VERSION 5.7 ;
  NOWIREEXTENSIONATPIN ON ;
  DIVIDERCHAR "/" ;
  BUSBITCHARS "[]" ;
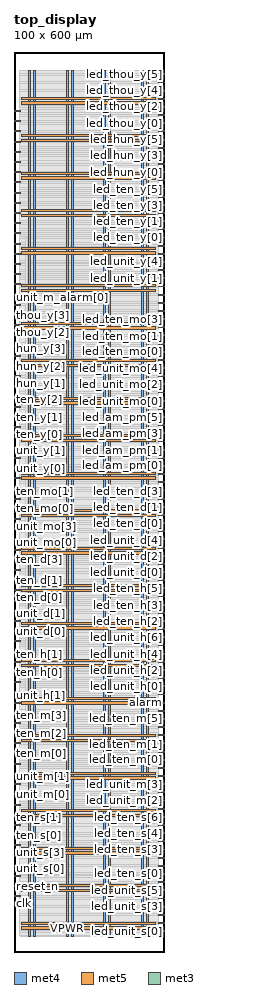
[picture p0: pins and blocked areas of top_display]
MACRO top_display
  CLASS BLOCK ;
  FOREIGN top_display ;
  ORIGIN 0.000 0.000 ;
  SIZE 100.000 BY 600.000 ;
  PIN VGND
    DIRECTION INOUT ;
    USE GROUND ;
    PORT
      LAYER met4 ;
        RECT 13.020 10.640 14.620 587.760 ;
    END
    PORT
      LAYER met4 ;
        RECT 38.020 10.640 39.620 587.760 ;
    END
    PORT
      LAYER met4 ;
        RECT 63.020 10.640 64.620 587.760 ;
    END
    PORT
      LAYER met4 ;
        RECT 88.020 10.640 89.620 587.760 ;
    END
    PORT
      LAYER met5 ;
        RECT 5.280 18.380 94.540 19.980 ;
    END
    PORT
      LAYER met5 ;
        RECT 5.280 43.380 94.540 44.980 ;
    END
    PORT
      LAYER met5 ;
        RECT 5.280 68.380 94.540 69.980 ;
    END
    PORT
      LAYER met5 ;
        RECT 5.280 93.380 94.540 94.980 ;
    END
    PORT
      LAYER met5 ;
        RECT 5.280 118.380 94.540 119.980 ;
    END
    PORT
      LAYER met5 ;
        RECT 5.280 143.380 94.540 144.980 ;
    END
    PORT
      LAYER met5 ;
        RECT 5.280 168.380 94.540 169.980 ;
    END
    PORT
      LAYER met5 ;
        RECT 5.280 193.380 94.540 194.980 ;
    END
    PORT
      LAYER met5 ;
        RECT 5.280 218.380 94.540 219.980 ;
    END
    PORT
      LAYER met5 ;
        RECT 5.280 243.380 94.540 244.980 ;
    END
    PORT
      LAYER met5 ;
        RECT 5.280 268.380 94.540 269.980 ;
    END
    PORT
      LAYER met5 ;
        RECT 5.280 293.380 94.540 294.980 ;
    END
    PORT
      LAYER met5 ;
        RECT 5.280 318.380 94.540 319.980 ;
    END
    PORT
      LAYER met5 ;
        RECT 5.280 343.380 94.540 344.980 ;
    END
    PORT
      LAYER met5 ;
        RECT 5.280 368.380 94.540 369.980 ;
    END
    PORT
      LAYER met5 ;
        RECT 5.280 393.380 94.540 394.980 ;
    END
    PORT
      LAYER met5 ;
        RECT 5.280 418.380 94.540 419.980 ;
    END
    PORT
      LAYER met5 ;
        RECT 5.280 443.380 94.540 444.980 ;
    END
    PORT
      LAYER met5 ;
        RECT 5.280 468.380 94.540 469.980 ;
    END
    PORT
      LAYER met5 ;
        RECT 5.280 493.380 94.540 494.980 ;
    END
    PORT
      LAYER met5 ;
        RECT 5.280 518.380 94.540 519.980 ;
    END
    PORT
      LAYER met5 ;
        RECT 5.280 543.380 94.540 544.980 ;
    END
    PORT
      LAYER met5 ;
        RECT 5.280 568.380 94.540 569.980 ;
    END
  END VGND
  PIN VPWR
    DIRECTION INOUT ;
    USE POWER ;
    PORT
      LAYER met4 ;
        RECT 9.720 10.640 11.320 587.760 ;
    END
    PORT
      LAYER met4 ;
        RECT 34.720 10.640 36.320 587.760 ;
    END
    PORT
      LAYER met4 ;
        RECT 59.720 10.640 61.320 587.760 ;
    END
    PORT
      LAYER met4 ;
        RECT 84.720 10.640 86.320 587.760 ;
    END
    PORT
      LAYER met5 ;
        RECT 5.280 15.080 94.540 16.680 ;
    END
    PORT
      LAYER met5 ;
        RECT 5.280 40.080 94.540 41.680 ;
    END
    PORT
      LAYER met5 ;
        RECT 5.280 65.080 94.540 66.680 ;
    END
    PORT
      LAYER met5 ;
        RECT 5.280 90.080 94.540 91.680 ;
    END
    PORT
      LAYER met5 ;
        RECT 5.280 115.080 94.540 116.680 ;
    END
    PORT
      LAYER met5 ;
        RECT 5.280 140.080 94.540 141.680 ;
    END
    PORT
      LAYER met5 ;
        RECT 5.280 165.080 94.540 166.680 ;
    END
    PORT
      LAYER met5 ;
        RECT 5.280 190.080 94.540 191.680 ;
    END
    PORT
      LAYER met5 ;
        RECT 5.280 215.080 94.540 216.680 ;
    END
    PORT
      LAYER met5 ;
        RECT 5.280 240.080 94.540 241.680 ;
    END
    PORT
      LAYER met5 ;
        RECT 5.280 265.080 94.540 266.680 ;
    END
    PORT
      LAYER met5 ;
        RECT 5.280 290.080 94.540 291.680 ;
    END
    PORT
      LAYER met5 ;
        RECT 5.280 315.080 94.540 316.680 ;
    END
    PORT
      LAYER met5 ;
        RECT 5.280 340.080 94.540 341.680 ;
    END
    PORT
      LAYER met5 ;
        RECT 5.280 365.080 94.540 366.680 ;
    END
    PORT
      LAYER met5 ;
        RECT 5.280 390.080 94.540 391.680 ;
    END
    PORT
      LAYER met5 ;
        RECT 5.280 415.080 94.540 416.680 ;
    END
    PORT
      LAYER met5 ;
        RECT 5.280 440.080 94.540 441.680 ;
    END
    PORT
      LAYER met5 ;
        RECT 5.280 465.080 94.540 466.680 ;
    END
    PORT
      LAYER met5 ;
        RECT 5.280 490.080 94.540 491.680 ;
    END
    PORT
      LAYER met5 ;
        RECT 5.280 515.080 94.540 516.680 ;
    END
    PORT
      LAYER met5 ;
        RECT 5.280 540.080 94.540 541.680 ;
    END
    PORT
      LAYER met5 ;
        RECT 5.280 565.080 94.540 566.680 ;
    END
  END VPWR
  PIN alarm
    DIRECTION OUTPUT ;
    USE SIGNAL ;
    ANTENNADIFFAREA 0.445500 ;
    PORT
      LAYER met3 ;
        RECT 96.000 165.960 100.000 166.560 ;
    END
  END alarm
  PIN clk
    DIRECTION INPUT ;
    USE SIGNAL ;
    PORT
      LAYER met3 ;
        RECT 0.000 36.760 4.000 37.360 ;
    END
  END clk
  PIN hun_y[0]
    DIRECTION INPUT ;
    USE SIGNAL ;
    ANTENNAGATEAREA 0.159000 ;
    PORT
      LAYER met3 ;
        RECT 0.000 376.760 4.000 377.360 ;
    END
  END hun_y[0]
  PIN hun_y[1]
    DIRECTION INPUT ;
    USE SIGNAL ;
    ANTENNAGATEAREA 0.213000 ;
    PORT
      LAYER met3 ;
        RECT 0.000 383.560 4.000 384.160 ;
    END
  END hun_y[1]
  PIN hun_y[2]
    DIRECTION INPUT ;
    USE SIGNAL ;
    ANTENNAGATEAREA 0.213000 ;
    PORT
      LAYER met3 ;
        RECT 0.000 390.360 4.000 390.960 ;
    END
  END hun_y[2]
  PIN hun_y[3]
    DIRECTION INPUT ;
    USE SIGNAL ;
    ANTENNAGATEAREA 0.213000 ;
    PORT
      LAYER met3 ;
        RECT 0.000 397.160 4.000 397.760 ;
    END
  END hun_y[3]
  PIN led_am_pm[0]
    DIRECTION OUTPUT ;
    USE SIGNAL ;
    ANTENNADIFFAREA 0.445500 ;
    PORT
      LAYER met3 ;
        RECT 96.000 323.720 100.000 324.320 ;
    END
  END led_am_pm[0]
  PIN led_am_pm[1]
    DIRECTION OUTPUT ;
    USE SIGNAL ;
    ANTENNADIFFAREA 0.445500 ;
    PORT
      LAYER met3 ;
        RECT 96.000 329.160 100.000 329.760 ;
    END
  END led_am_pm[1]
  PIN led_am_pm[2]
    DIRECTION OUTPUT ;
    USE SIGNAL ;
    ANTENNADIFFAREA 0.445500 ;
    PORT
      LAYER met3 ;
        RECT 96.000 334.600 100.000 335.200 ;
    END
  END led_am_pm[2]
  PIN led_am_pm[3]
    DIRECTION OUTPUT ;
    USE SIGNAL ;
    ANTENNADIFFAREA 0.445500 ;
    PORT
      LAYER met3 ;
        RECT 96.000 340.040 100.000 340.640 ;
    END
  END led_am_pm[3]
  PIN led_am_pm[4]
    DIRECTION OUTPUT ;
    USE SIGNAL ;
    PORT
      LAYER met3 ;
        RECT 96.000 345.480 100.000 346.080 ;
    END
  END led_am_pm[4]
  PIN led_am_pm[5]
    DIRECTION OUTPUT ;
    USE SIGNAL ;
    ANTENNADIFFAREA 0.445500 ;
    PORT
      LAYER met3 ;
        RECT 96.000 350.920 100.000 351.520 ;
    END
  END led_am_pm[5]
  PIN led_am_pm[6]
    DIRECTION OUTPUT ;
    USE SIGNAL ;
    ANTENNADIFFAREA 0.445500 ;
    PORT
      LAYER met3 ;
        RECT 96.000 356.360 100.000 356.960 ;
    END
  END led_am_pm[6]
  PIN led_hun_y[0]
    DIRECTION OUTPUT ;
    USE SIGNAL ;
    ANTENNADIFFAREA 0.445500 ;
    PORT
      LAYER met3 ;
        RECT 96.000 514.120 100.000 514.720 ;
    END
  END led_hun_y[0]
  PIN led_hun_y[1]
    DIRECTION OUTPUT ;
    USE SIGNAL ;
    ANTENNADIFFAREA 0.445500 ;
    PORT
      LAYER met3 ;
        RECT 96.000 519.560 100.000 520.160 ;
    END
  END led_hun_y[1]
  PIN led_hun_y[2]
    DIRECTION OUTPUT ;
    USE SIGNAL ;
    ANTENNADIFFAREA 0.445500 ;
    PORT
      LAYER met3 ;
        RECT 96.000 525.000 100.000 525.600 ;
    END
  END led_hun_y[2]
  PIN led_hun_y[3]
    DIRECTION OUTPUT ;
    USE SIGNAL ;
    ANTENNADIFFAREA 0.445500 ;
    PORT
      LAYER met3 ;
        RECT 96.000 530.440 100.000 531.040 ;
    END
  END led_hun_y[3]
  PIN led_hun_y[4]
    DIRECTION OUTPUT ;
    USE SIGNAL ;
    ANTENNADIFFAREA 0.445500 ;
    PORT
      LAYER met3 ;
        RECT 96.000 535.880 100.000 536.480 ;
    END
  END led_hun_y[4]
  PIN led_hun_y[5]
    DIRECTION OUTPUT ;
    USE SIGNAL ;
    ANTENNADIFFAREA 0.445500 ;
    PORT
      LAYER met3 ;
        RECT 96.000 541.320 100.000 541.920 ;
    END
  END led_hun_y[5]
  PIN led_hun_y[6]
    DIRECTION OUTPUT ;
    USE SIGNAL ;
    ANTENNADIFFAREA 0.445500 ;
    PORT
      LAYER met3 ;
        RECT 96.000 546.760 100.000 547.360 ;
    END
  END led_hun_y[6]
  PIN led_ten_d[0]
    DIRECTION OUTPUT ;
    USE SIGNAL ;
    ANTENNADIFFAREA 0.445500 ;
    PORT
      LAYER met3 ;
        RECT 96.000 285.640 100.000 286.240 ;
    END
  END led_ten_d[0]
  PIN led_ten_d[1]
    DIRECTION OUTPUT ;
    USE SIGNAL ;
    ANTENNADIFFAREA 0.445500 ;
    PORT
      LAYER met3 ;
        RECT 96.000 291.080 100.000 291.680 ;
    END
  END led_ten_d[1]
  PIN led_ten_d[2]
    DIRECTION OUTPUT ;
    USE SIGNAL ;
    ANTENNADIFFAREA 0.445500 ;
    PORT
      LAYER met3 ;
        RECT 96.000 296.520 100.000 297.120 ;
    END
  END led_ten_d[2]
  PIN led_ten_d[3]
    DIRECTION OUTPUT ;
    USE SIGNAL ;
    ANTENNADIFFAREA 0.445500 ;
    PORT
      LAYER met3 ;
        RECT 96.000 301.960 100.000 302.560 ;
    END
  END led_ten_d[3]
  PIN led_ten_d[4]
    DIRECTION OUTPUT ;
    USE SIGNAL ;
    ANTENNADIFFAREA 0.445500 ;
    PORT
      LAYER met3 ;
        RECT 96.000 307.400 100.000 308.000 ;
    END
  END led_ten_d[4]
  PIN led_ten_d[5]
    DIRECTION OUTPUT ;
    USE SIGNAL ;
    ANTENNADIFFAREA 0.445500 ;
    PORT
      LAYER met3 ;
        RECT 96.000 312.840 100.000 313.440 ;
    END
  END led_ten_d[5]
  PIN led_ten_d[6]
    DIRECTION OUTPUT ;
    USE SIGNAL ;
    ANTENNADIFFAREA 0.445500 ;
    PORT
      LAYER met3 ;
        RECT 96.000 318.280 100.000 318.880 ;
    END
  END led_ten_d[6]
  PIN led_ten_h[0]
    DIRECTION OUTPUT ;
    USE SIGNAL ;
    ANTENNADIFFAREA 0.445500 ;
    PORT
      LAYER met3 ;
        RECT 96.000 209.480 100.000 210.080 ;
    END
  END led_ten_h[0]
  PIN led_ten_h[1]
    DIRECTION OUTPUT ;
    USE SIGNAL ;
    ANTENNADIFFAREA 0.445500 ;
    PORT
      LAYER met3 ;
        RECT 96.000 214.920 100.000 215.520 ;
    END
  END led_ten_h[1]
  PIN led_ten_h[2]
    DIRECTION OUTPUT ;
    USE SIGNAL ;
    ANTENNADIFFAREA 0.445500 ;
    PORT
      LAYER met3 ;
        RECT 96.000 220.360 100.000 220.960 ;
    END
  END led_ten_h[2]
  PIN led_ten_h[3]
    DIRECTION OUTPUT ;
    USE SIGNAL ;
    ANTENNADIFFAREA 0.445500 ;
    PORT
      LAYER met3 ;
        RECT 96.000 225.800 100.000 226.400 ;
    END
  END led_ten_h[3]
  PIN led_ten_h[4]
    DIRECTION OUTPUT ;
    USE SIGNAL ;
    ANTENNADIFFAREA 0.445500 ;
    PORT
      LAYER met3 ;
        RECT 96.000 231.240 100.000 231.840 ;
    END
  END led_ten_h[4]
  PIN led_ten_h[5]
    DIRECTION OUTPUT ;
    USE SIGNAL ;
    ANTENNADIFFAREA 0.445500 ;
    PORT
      LAYER met3 ;
        RECT 96.000 236.680 100.000 237.280 ;
    END
  END led_ten_h[5]
  PIN led_ten_h[6]
    DIRECTION OUTPUT ;
    USE SIGNAL ;
    ANTENNADIFFAREA 0.445500 ;
    PORT
      LAYER met3 ;
        RECT 96.000 242.120 100.000 242.720 ;
    END
  END led_ten_h[6]
  PIN led_ten_m[0]
    DIRECTION OUTPUT ;
    USE SIGNAL ;
    ANTENNADIFFAREA 0.445500 ;
    PORT
      LAYER met3 ;
        RECT 96.000 127.880 100.000 128.480 ;
    END
  END led_ten_m[0]
  PIN led_ten_m[1]
    DIRECTION OUTPUT ;
    USE SIGNAL ;
    ANTENNADIFFAREA 0.445500 ;
    PORT
      LAYER met3 ;
        RECT 96.000 133.320 100.000 133.920 ;
    END
  END led_ten_m[1]
  PIN led_ten_m[2]
    DIRECTION OUTPUT ;
    USE SIGNAL ;
    ANTENNADIFFAREA 0.445500 ;
    PORT
      LAYER met3 ;
        RECT 96.000 138.760 100.000 139.360 ;
    END
  END led_ten_m[2]
  PIN led_ten_m[3]
    DIRECTION OUTPUT ;
    USE SIGNAL ;
    ANTENNADIFFAREA 0.445500 ;
    PORT
      LAYER met3 ;
        RECT 96.000 144.200 100.000 144.800 ;
    END
  END led_ten_m[3]
  PIN led_ten_m[4]
    DIRECTION OUTPUT ;
    USE SIGNAL ;
    ANTENNADIFFAREA 0.445500 ;
    PORT
      LAYER met3 ;
        RECT 96.000 149.640 100.000 150.240 ;
    END
  END led_ten_m[4]
  PIN led_ten_m[5]
    DIRECTION OUTPUT ;
    USE SIGNAL ;
    ANTENNADIFFAREA 0.445500 ;
    PORT
      LAYER met3 ;
        RECT 96.000 155.080 100.000 155.680 ;
    END
  END led_ten_m[5]
  PIN led_ten_m[6]
    DIRECTION OUTPUT ;
    USE SIGNAL ;
    ANTENNADIFFAREA 0.445500 ;
    PORT
      LAYER met3 ;
        RECT 96.000 160.520 100.000 161.120 ;
    END
  END led_ten_m[6]
  PIN led_ten_mo[0]
    DIRECTION OUTPUT ;
    USE SIGNAL ;
    ANTENNADIFFAREA 0.445500 ;
    PORT
      LAYER met3 ;
        RECT 96.000 399.880 100.000 400.480 ;
    END
  END led_ten_mo[0]
  PIN led_ten_mo[1]
    DIRECTION OUTPUT ;
    USE SIGNAL ;
    ANTENNADIFFAREA 0.445500 ;
    PORT
      LAYER met3 ;
        RECT 96.000 405.320 100.000 405.920 ;
    END
  END led_ten_mo[1]
  PIN led_ten_mo[2]
    DIRECTION OUTPUT ;
    USE SIGNAL ;
    ANTENNADIFFAREA 0.445500 ;
    PORT
      LAYER met3 ;
        RECT 96.000 410.760 100.000 411.360 ;
    END
  END led_ten_mo[2]
  PIN led_ten_mo[3]
    DIRECTION OUTPUT ;
    USE SIGNAL ;
    ANTENNADIFFAREA 0.445500 ;
    PORT
      LAYER met3 ;
        RECT 96.000 416.200 100.000 416.800 ;
    END
  END led_ten_mo[3]
  PIN led_ten_mo[4]
    DIRECTION OUTPUT ;
    USE SIGNAL ;
    ANTENNADIFFAREA 0.445500 ;
    PORT
      LAYER met3 ;
        RECT 96.000 421.640 100.000 422.240 ;
    END
  END led_ten_mo[4]
  PIN led_ten_mo[5]
    DIRECTION OUTPUT ;
    USE SIGNAL ;
    ANTENNADIFFAREA 0.445500 ;
    PORT
      LAYER met3 ;
        RECT 96.000 427.080 100.000 427.680 ;
    END
  END led_ten_mo[5]
  PIN led_ten_mo[6]
    DIRECTION OUTPUT ;
    USE SIGNAL ;
    ANTENNADIFFAREA 0.445500 ;
    PORT
      LAYER met3 ;
        RECT 96.000 432.520 100.000 433.120 ;
    END
  END led_ten_mo[6]
  PIN led_ten_s[0]
    DIRECTION OUTPUT ;
    USE SIGNAL ;
    ANTENNADIFFAREA 0.445500 ;
    PORT
      LAYER met3 ;
        RECT 96.000 51.720 100.000 52.320 ;
    END
  END led_ten_s[0]
  PIN led_ten_s[1]
    DIRECTION OUTPUT ;
    USE SIGNAL ;
    ANTENNADIFFAREA 0.445500 ;
    PORT
      LAYER met3 ;
        RECT 96.000 57.160 100.000 57.760 ;
    END
  END led_ten_s[1]
  PIN led_ten_s[2]
    DIRECTION OUTPUT ;
    USE SIGNAL ;
    ANTENNADIFFAREA 0.445500 ;
    PORT
      LAYER met3 ;
        RECT 96.000 62.600 100.000 63.200 ;
    END
  END led_ten_s[2]
  PIN led_ten_s[3]
    DIRECTION OUTPUT ;
    USE SIGNAL ;
    ANTENNADIFFAREA 0.445500 ;
    PORT
      LAYER met3 ;
        RECT 96.000 68.040 100.000 68.640 ;
    END
  END led_ten_s[3]
  PIN led_ten_s[4]
    DIRECTION OUTPUT ;
    USE SIGNAL ;
    ANTENNADIFFAREA 0.445500 ;
    PORT
      LAYER met3 ;
        RECT 96.000 73.480 100.000 74.080 ;
    END
  END led_ten_s[4]
  PIN led_ten_s[5]
    DIRECTION OUTPUT ;
    USE SIGNAL ;
    ANTENNADIFFAREA 0.445500 ;
    PORT
      LAYER met3 ;
        RECT 96.000 78.920 100.000 79.520 ;
    END
  END led_ten_s[5]
  PIN led_ten_s[6]
    DIRECTION OUTPUT ;
    USE SIGNAL ;
    ANTENNADIFFAREA 0.445500 ;
    PORT
      LAYER met3 ;
        RECT 96.000 84.360 100.000 84.960 ;
    END
  END led_ten_s[6]
  PIN led_ten_y[0]
    DIRECTION OUTPUT ;
    USE SIGNAL ;
    ANTENNADIFFAREA 0.445500 ;
    PORT
      LAYER met3 ;
        RECT 96.000 476.040 100.000 476.640 ;
    END
  END led_ten_y[0]
  PIN led_ten_y[1]
    DIRECTION OUTPUT ;
    USE SIGNAL ;
    ANTENNADIFFAREA 0.445500 ;
    PORT
      LAYER met3 ;
        RECT 96.000 481.480 100.000 482.080 ;
    END
  END led_ten_y[1]
  PIN led_ten_y[2]
    DIRECTION OUTPUT ;
    USE SIGNAL ;
    ANTENNADIFFAREA 0.445500 ;
    PORT
      LAYER met3 ;
        RECT 96.000 486.920 100.000 487.520 ;
    END
  END led_ten_y[2]
  PIN led_ten_y[3]
    DIRECTION OUTPUT ;
    USE SIGNAL ;
    ANTENNADIFFAREA 0.445500 ;
    PORT
      LAYER met3 ;
        RECT 96.000 492.360 100.000 492.960 ;
    END
  END led_ten_y[3]
  PIN led_ten_y[4]
    DIRECTION OUTPUT ;
    USE SIGNAL ;
    ANTENNADIFFAREA 0.445500 ;
    PORT
      LAYER met3 ;
        RECT 96.000 497.800 100.000 498.400 ;
    END
  END led_ten_y[4]
  PIN led_ten_y[5]
    DIRECTION OUTPUT ;
    USE SIGNAL ;
    ANTENNADIFFAREA 0.445500 ;
    PORT
      LAYER met3 ;
        RECT 96.000 503.240 100.000 503.840 ;
    END
  END led_ten_y[5]
  PIN led_ten_y[6]
    DIRECTION OUTPUT ;
    USE SIGNAL ;
    ANTENNADIFFAREA 0.445500 ;
    PORT
      LAYER met3 ;
        RECT 96.000 508.680 100.000 509.280 ;
    END
  END led_ten_y[6]
  PIN led_thou_y[0]
    DIRECTION OUTPUT ;
    USE SIGNAL ;
    ANTENNADIFFAREA 0.445500 ;
    PORT
      LAYER met3 ;
        RECT 96.000 552.200 100.000 552.800 ;
    END
  END led_thou_y[0]
  PIN led_thou_y[1]
    DIRECTION OUTPUT ;
    USE SIGNAL ;
    ANTENNADIFFAREA 0.445500 ;
    PORT
      LAYER met3 ;
        RECT 96.000 557.640 100.000 558.240 ;
    END
  END led_thou_y[1]
  PIN led_thou_y[2]
    DIRECTION OUTPUT ;
    USE SIGNAL ;
    ANTENNADIFFAREA 0.445500 ;
    PORT
      LAYER met3 ;
        RECT 96.000 563.080 100.000 563.680 ;
    END
  END led_thou_y[2]
  PIN led_thou_y[3]
    DIRECTION OUTPUT ;
    USE SIGNAL ;
    ANTENNADIFFAREA 0.445500 ;
    PORT
      LAYER met3 ;
        RECT 96.000 568.520 100.000 569.120 ;
    END
  END led_thou_y[3]
  PIN led_thou_y[4]
    DIRECTION OUTPUT ;
    USE SIGNAL ;
    ANTENNADIFFAREA 0.445500 ;
    PORT
      LAYER met3 ;
        RECT 96.000 573.960 100.000 574.560 ;
    END
  END led_thou_y[4]
  PIN led_thou_y[5]
    DIRECTION OUTPUT ;
    USE SIGNAL ;
    ANTENNADIFFAREA 0.445500 ;
    PORT
      LAYER met3 ;
        RECT 96.000 579.400 100.000 580.000 ;
    END
  END led_thou_y[5]
  PIN led_thou_y[6]
    DIRECTION OUTPUT ;
    USE SIGNAL ;
    ANTENNADIFFAREA 0.445500 ;
    PORT
      LAYER met3 ;
        RECT 96.000 584.840 100.000 585.440 ;
    END
  END led_thou_y[6]
  PIN led_unit_d[0]
    DIRECTION OUTPUT ;
    USE SIGNAL ;
    ANTENNADIFFAREA 0.445500 ;
    PORT
      LAYER met3 ;
        RECT 96.000 247.560 100.000 248.160 ;
    END
  END led_unit_d[0]
  PIN led_unit_d[1]
    DIRECTION OUTPUT ;
    USE SIGNAL ;
    ANTENNADIFFAREA 0.445500 ;
    PORT
      LAYER met3 ;
        RECT 96.000 253.000 100.000 253.600 ;
    END
  END led_unit_d[1]
  PIN led_unit_d[2]
    DIRECTION OUTPUT ;
    USE SIGNAL ;
    ANTENNADIFFAREA 0.445500 ;
    PORT
      LAYER met3 ;
        RECT 96.000 258.440 100.000 259.040 ;
    END
  END led_unit_d[2]
  PIN led_unit_d[3]
    DIRECTION OUTPUT ;
    USE SIGNAL ;
    ANTENNADIFFAREA 0.445500 ;
    PORT
      LAYER met3 ;
        RECT 96.000 263.880 100.000 264.480 ;
    END
  END led_unit_d[3]
  PIN led_unit_d[4]
    DIRECTION OUTPUT ;
    USE SIGNAL ;
    ANTENNADIFFAREA 0.445500 ;
    PORT
      LAYER met3 ;
        RECT 96.000 269.320 100.000 269.920 ;
    END
  END led_unit_d[4]
  PIN led_unit_d[5]
    DIRECTION OUTPUT ;
    USE SIGNAL ;
    ANTENNADIFFAREA 0.445500 ;
    PORT
      LAYER met3 ;
        RECT 96.000 274.760 100.000 275.360 ;
    END
  END led_unit_d[5]
  PIN led_unit_d[6]
    DIRECTION OUTPUT ;
    USE SIGNAL ;
    ANTENNADIFFAREA 0.445500 ;
    PORT
      LAYER met3 ;
        RECT 96.000 280.200 100.000 280.800 ;
    END
  END led_unit_d[6]
  PIN led_unit_h[0]
    DIRECTION OUTPUT ;
    USE SIGNAL ;
    ANTENNADIFFAREA 0.445500 ;
    PORT
      LAYER met3 ;
        RECT 96.000 171.400 100.000 172.000 ;
    END
  END led_unit_h[0]
  PIN led_unit_h[1]
    DIRECTION OUTPUT ;
    USE SIGNAL ;
    ANTENNADIFFAREA 0.445500 ;
    PORT
      LAYER met3 ;
        RECT 96.000 176.840 100.000 177.440 ;
    END
  END led_unit_h[1]
  PIN led_unit_h[2]
    DIRECTION OUTPUT ;
    USE SIGNAL ;
    ANTENNADIFFAREA 0.445500 ;
    PORT
      LAYER met3 ;
        RECT 96.000 182.280 100.000 182.880 ;
    END
  END led_unit_h[2]
  PIN led_unit_h[3]
    DIRECTION OUTPUT ;
    USE SIGNAL ;
    ANTENNADIFFAREA 0.445500 ;
    PORT
      LAYER met3 ;
        RECT 96.000 187.720 100.000 188.320 ;
    END
  END led_unit_h[3]
  PIN led_unit_h[4]
    DIRECTION OUTPUT ;
    USE SIGNAL ;
    ANTENNADIFFAREA 0.445500 ;
    PORT
      LAYER met3 ;
        RECT 96.000 193.160 100.000 193.760 ;
    END
  END led_unit_h[4]
  PIN led_unit_h[5]
    DIRECTION OUTPUT ;
    USE SIGNAL ;
    ANTENNADIFFAREA 0.445500 ;
    PORT
      LAYER met3 ;
        RECT 96.000 198.600 100.000 199.200 ;
    END
  END led_unit_h[5]
  PIN led_unit_h[6]
    DIRECTION OUTPUT ;
    USE SIGNAL ;
    ANTENNADIFFAREA 0.445500 ;
    PORT
      LAYER met3 ;
        RECT 96.000 204.040 100.000 204.640 ;
    END
  END led_unit_h[6]
  PIN led_unit_m[0]
    DIRECTION OUTPUT ;
    USE SIGNAL ;
    ANTENNADIFFAREA 0.445500 ;
    PORT
      LAYER met3 ;
        RECT 96.000 89.800 100.000 90.400 ;
    END
  END led_unit_m[0]
  PIN led_unit_m[1]
    DIRECTION OUTPUT ;
    USE SIGNAL ;
    ANTENNADIFFAREA 0.445500 ;
    PORT
      LAYER met3 ;
        RECT 96.000 95.240 100.000 95.840 ;
    END
  END led_unit_m[1]
  PIN led_unit_m[2]
    DIRECTION OUTPUT ;
    USE SIGNAL ;
    ANTENNADIFFAREA 0.445500 ;
    PORT
      LAYER met3 ;
        RECT 96.000 100.680 100.000 101.280 ;
    END
  END led_unit_m[2]
  PIN led_unit_m[3]
    DIRECTION OUTPUT ;
    USE SIGNAL ;
    ANTENNADIFFAREA 0.445500 ;
    PORT
      LAYER met3 ;
        RECT 96.000 106.120 100.000 106.720 ;
    END
  END led_unit_m[3]
  PIN led_unit_m[4]
    DIRECTION OUTPUT ;
    USE SIGNAL ;
    ANTENNADIFFAREA 0.445500 ;
    PORT
      LAYER met3 ;
        RECT 96.000 111.560 100.000 112.160 ;
    END
  END led_unit_m[4]
  PIN led_unit_m[5]
    DIRECTION OUTPUT ;
    USE SIGNAL ;
    ANTENNADIFFAREA 0.445500 ;
    PORT
      LAYER met3 ;
        RECT 96.000 117.000 100.000 117.600 ;
    END
  END led_unit_m[5]
  PIN led_unit_m[6]
    DIRECTION OUTPUT ;
    USE SIGNAL ;
    ANTENNADIFFAREA 0.445500 ;
    PORT
      LAYER met3 ;
        RECT 96.000 122.440 100.000 123.040 ;
    END
  END led_unit_m[6]
  PIN led_unit_mo[0]
    DIRECTION OUTPUT ;
    USE SIGNAL ;
    ANTENNADIFFAREA 0.445500 ;
    PORT
      LAYER met3 ;
        RECT 96.000 361.800 100.000 362.400 ;
    END
  END led_unit_mo[0]
  PIN led_unit_mo[1]
    DIRECTION OUTPUT ;
    USE SIGNAL ;
    ANTENNADIFFAREA 0.445500 ;
    PORT
      LAYER met3 ;
        RECT 96.000 367.240 100.000 367.840 ;
    END
  END led_unit_mo[1]
  PIN led_unit_mo[2]
    DIRECTION OUTPUT ;
    USE SIGNAL ;
    ANTENNADIFFAREA 0.445500 ;
    PORT
      LAYER met3 ;
        RECT 96.000 372.680 100.000 373.280 ;
    END
  END led_unit_mo[2]
  PIN led_unit_mo[3]
    DIRECTION OUTPUT ;
    USE SIGNAL ;
    ANTENNADIFFAREA 0.445500 ;
    PORT
      LAYER met3 ;
        RECT 96.000 378.120 100.000 378.720 ;
    END
  END led_unit_mo[3]
  PIN led_unit_mo[4]
    DIRECTION OUTPUT ;
    USE SIGNAL ;
    ANTENNADIFFAREA 0.445500 ;
    PORT
      LAYER met3 ;
        RECT 96.000 383.560 100.000 384.160 ;
    END
  END led_unit_mo[4]
  PIN led_unit_mo[5]
    DIRECTION OUTPUT ;
    USE SIGNAL ;
    ANTENNADIFFAREA 0.445500 ;
    PORT
      LAYER met3 ;
        RECT 96.000 389.000 100.000 389.600 ;
    END
  END led_unit_mo[5]
  PIN led_unit_mo[6]
    DIRECTION OUTPUT ;
    USE SIGNAL ;
    ANTENNADIFFAREA 0.445500 ;
    PORT
      LAYER met3 ;
        RECT 96.000 394.440 100.000 395.040 ;
    END
  END led_unit_mo[6]
  PIN led_unit_s[0]
    DIRECTION OUTPUT ;
    USE SIGNAL ;
    ANTENNADIFFAREA 0.445500 ;
    PORT
      LAYER met3 ;
        RECT 96.000 13.640 100.000 14.240 ;
    END
  END led_unit_s[0]
  PIN led_unit_s[1]
    DIRECTION OUTPUT ;
    USE SIGNAL ;
    ANTENNADIFFAREA 0.445500 ;
    PORT
      LAYER met3 ;
        RECT 96.000 19.080 100.000 19.680 ;
    END
  END led_unit_s[1]
  PIN led_unit_s[2]
    DIRECTION OUTPUT ;
    USE SIGNAL ;
    ANTENNADIFFAREA 0.445500 ;
    PORT
      LAYER met3 ;
        RECT 96.000 24.520 100.000 25.120 ;
    END
  END led_unit_s[2]
  PIN led_unit_s[3]
    DIRECTION OUTPUT ;
    USE SIGNAL ;
    ANTENNADIFFAREA 0.445500 ;
    PORT
      LAYER met3 ;
        RECT 96.000 29.960 100.000 30.560 ;
    END
  END led_unit_s[3]
  PIN led_unit_s[4]
    DIRECTION OUTPUT ;
    USE SIGNAL ;
    ANTENNADIFFAREA 0.445500 ;
    PORT
      LAYER met3 ;
        RECT 96.000 35.400 100.000 36.000 ;
    END
  END led_unit_s[4]
  PIN led_unit_s[5]
    DIRECTION OUTPUT ;
    USE SIGNAL ;
    ANTENNADIFFAREA 0.445500 ;
    PORT
      LAYER met3 ;
        RECT 96.000 40.840 100.000 41.440 ;
    END
  END led_unit_s[5]
  PIN led_unit_s[6]
    DIRECTION OUTPUT ;
    USE SIGNAL ;
    ANTENNADIFFAREA 0.445500 ;
    PORT
      LAYER met3 ;
        RECT 96.000 46.280 100.000 46.880 ;
    END
  END led_unit_s[6]
  PIN led_unit_y[0]
    DIRECTION OUTPUT ;
    USE SIGNAL ;
    ANTENNADIFFAREA 0.445500 ;
    PORT
      LAYER met3 ;
        RECT 96.000 437.960 100.000 438.560 ;
    END
  END led_unit_y[0]
  PIN led_unit_y[1]
    DIRECTION OUTPUT ;
    USE SIGNAL ;
    ANTENNADIFFAREA 0.445500 ;
    PORT
      LAYER met3 ;
        RECT 96.000 443.400 100.000 444.000 ;
    END
  END led_unit_y[1]
  PIN led_unit_y[2]
    DIRECTION OUTPUT ;
    USE SIGNAL ;
    ANTENNADIFFAREA 0.445500 ;
    PORT
      LAYER met3 ;
        RECT 96.000 448.840 100.000 449.440 ;
    END
  END led_unit_y[2]
  PIN led_unit_y[3]
    DIRECTION OUTPUT ;
    USE SIGNAL ;
    ANTENNADIFFAREA 0.445500 ;
    PORT
      LAYER met3 ;
        RECT 96.000 454.280 100.000 454.880 ;
    END
  END led_unit_y[3]
  PIN led_unit_y[4]
    DIRECTION OUTPUT ;
    USE SIGNAL ;
    ANTENNADIFFAREA 0.445500 ;
    PORT
      LAYER met3 ;
        RECT 96.000 459.720 100.000 460.320 ;
    END
  END led_unit_y[4]
  PIN led_unit_y[5]
    DIRECTION OUTPUT ;
    USE SIGNAL ;
    ANTENNADIFFAREA 0.445500 ;
    PORT
      LAYER met3 ;
        RECT 96.000 465.160 100.000 465.760 ;
    END
  END led_unit_y[5]
  PIN led_unit_y[6]
    DIRECTION OUTPUT ;
    USE SIGNAL ;
    ANTENNADIFFAREA 0.445500 ;
    PORT
      LAYER met3 ;
        RECT 96.000 470.600 100.000 471.200 ;
    END
  END led_unit_y[6]
  PIN mode_alarm[0]
    DIRECTION INPUT ;
    USE SIGNAL ;
    PORT
      LAYER met3 ;
        RECT 0.000 539.960 4.000 540.560 ;
    END
  END mode_alarm[0]
  PIN mode_alarm[1]
    DIRECTION INPUT ;
    USE SIGNAL ;
    PORT
      LAYER met3 ;
        RECT 0.000 546.760 4.000 547.360 ;
    END
  END mode_alarm[1]
  PIN mode_display[0]
    DIRECTION INPUT ;
    USE SIGNAL ;
    ANTENNAGATEAREA 0.196500 ;
    PORT
      LAYER met3 ;
        RECT 0.000 553.560 4.000 554.160 ;
    END
  END mode_display[0]
  PIN mode_display[1]
    DIRECTION INPUT ;
    USE SIGNAL ;
    ANTENNAGATEAREA 0.196500 ;
    PORT
      LAYER met3 ;
        RECT 0.000 560.360 4.000 560.960 ;
    END
  END mode_display[1]
  PIN reset_n
    DIRECTION INPUT ;
    USE SIGNAL ;
    PORT
      LAYER met3 ;
        RECT 0.000 43.560 4.000 44.160 ;
    END
  END reset_n
  PIN ten_d[0]
    DIRECTION INPUT ;
    USE SIGNAL ;
    ANTENNAGATEAREA 0.213000 ;
    PORT
      LAYER met3 ;
        RECT 0.000 240.760 4.000 241.360 ;
    END
  END ten_d[0]
  PIN ten_d[1]
    DIRECTION INPUT ;
    USE SIGNAL ;
    ANTENNAGATEAREA 0.159000 ;
    PORT
      LAYER met3 ;
        RECT 0.000 247.560 4.000 248.160 ;
    END
  END ten_d[1]
  PIN ten_d[2]
    DIRECTION INPUT ;
    USE SIGNAL ;
    ANTENNAGATEAREA 0.213000 ;
    PORT
      LAYER met3 ;
        RECT 0.000 254.360 4.000 254.960 ;
    END
  END ten_d[2]
  PIN ten_d[3]
    DIRECTION INPUT ;
    USE SIGNAL ;
    ANTENNAGATEAREA 0.159000 ;
    PORT
      LAYER met3 ;
        RECT 0.000 261.160 4.000 261.760 ;
    END
  END ten_d[3]
  PIN ten_h[0]
    DIRECTION INPUT ;
    USE SIGNAL ;
    ANTENNAGATEAREA 0.159000 ;
    PORT
      LAYER met3 ;
        RECT 0.000 186.360 4.000 186.960 ;
    END
  END ten_h[0]
  PIN ten_h[1]
    DIRECTION INPUT ;
    USE SIGNAL ;
    ANTENNAGATEAREA 0.213000 ;
    PORT
      LAYER met3 ;
        RECT 0.000 193.160 4.000 193.760 ;
    END
  END ten_h[1]
  PIN ten_h[2]
    DIRECTION INPUT ;
    USE SIGNAL ;
    ANTENNAGATEAREA 0.159000 ;
    PORT
      LAYER met3 ;
        RECT 0.000 199.960 4.000 200.560 ;
    END
  END ten_h[2]
  PIN ten_h[3]
    DIRECTION INPUT ;
    USE SIGNAL ;
    ANTENNAGATEAREA 0.213000 ;
    PORT
      LAYER met3 ;
        RECT 0.000 206.760 4.000 207.360 ;
    END
  END ten_h[3]
  PIN ten_h_alarm[0]
    DIRECTION INPUT ;
    USE SIGNAL ;
    ANTENNAGATEAREA 0.213000 ;
    PORT
      LAYER met3 ;
        RECT 0.000 512.760 4.000 513.360 ;
    END
  END ten_h_alarm[0]
  PIN ten_h_alarm[1]
    DIRECTION INPUT ;
    USE SIGNAL ;
    ANTENNAGATEAREA 0.159000 ;
    PORT
      LAYER met3 ;
        RECT 0.000 519.560 4.000 520.160 ;
    END
  END ten_h_alarm[1]
  PIN ten_h_alarm[2]
    DIRECTION INPUT ;
    USE SIGNAL ;
    ANTENNAGATEAREA 0.159000 ;
    PORT
      LAYER met3 ;
        RECT 0.000 526.360 4.000 526.960 ;
    END
  END ten_h_alarm[2]
  PIN ten_h_alarm[3]
    DIRECTION INPUT ;
    USE SIGNAL ;
    ANTENNAGATEAREA 0.159000 ;
    PORT
      LAYER met3 ;
        RECT 0.000 533.160 4.000 533.760 ;
    END
  END ten_h_alarm[3]
  PIN ten_m[0]
    DIRECTION INPUT ;
    USE SIGNAL ;
    ANTENNAGATEAREA 0.159000 ;
    PORT
      LAYER met3 ;
        RECT 0.000 131.960 4.000 132.560 ;
    END
  END ten_m[0]
  PIN ten_m[1]
    DIRECTION INPUT ;
    USE SIGNAL ;
    ANTENNAGATEAREA 0.213000 ;
    PORT
      LAYER met3 ;
        RECT 0.000 138.760 4.000 139.360 ;
    END
  END ten_m[1]
  PIN ten_m[2]
    DIRECTION INPUT ;
    USE SIGNAL ;
    ANTENNAGATEAREA 0.213000 ;
    PORT
      LAYER met3 ;
        RECT 0.000 145.560 4.000 146.160 ;
    END
  END ten_m[2]
  PIN ten_m[3]
    DIRECTION INPUT ;
    USE SIGNAL ;
    ANTENNAGATEAREA 0.196500 ;
    PORT
      LAYER met3 ;
        RECT 0.000 152.360 4.000 152.960 ;
    END
  END ten_m[3]
  PIN ten_m_alarm[0]
    DIRECTION INPUT ;
    USE SIGNAL ;
    ANTENNAGATEAREA 0.159000 ;
    PORT
      LAYER met3 ;
        RECT 0.000 458.360 4.000 458.960 ;
    END
  END ten_m_alarm[0]
  PIN ten_m_alarm[1]
    DIRECTION INPUT ;
    USE SIGNAL ;
    ANTENNAGATEAREA 0.213000 ;
    PORT
      LAYER met3 ;
        RECT 0.000 465.160 4.000 465.760 ;
    END
  END ten_m_alarm[1]
  PIN ten_m_alarm[2]
    DIRECTION INPUT ;
    USE SIGNAL ;
    ANTENNAGATEAREA 0.213000 ;
    PORT
      LAYER met3 ;
        RECT 0.000 471.960 4.000 472.560 ;
    END
  END ten_m_alarm[2]
  PIN ten_m_alarm[3]
    DIRECTION INPUT ;
    USE SIGNAL ;
    ANTENNAGATEAREA 0.159000 ;
    PORT
      LAYER met3 ;
        RECT 0.000 478.760 4.000 479.360 ;
    END
  END ten_m_alarm[3]
  PIN ten_mo[0]
    DIRECTION INPUT ;
    USE SIGNAL ;
    ANTENNAGATEAREA 0.159000 ;
    PORT
      LAYER met3 ;
        RECT 0.000 295.160 4.000 295.760 ;
    END
  END ten_mo[0]
  PIN ten_mo[1]
    DIRECTION INPUT ;
    USE SIGNAL ;
    ANTENNAGATEAREA 0.159000 ;
    PORT
      LAYER met3 ;
        RECT 0.000 301.960 4.000 302.560 ;
    END
  END ten_mo[1]
  PIN ten_mo[2]
    DIRECTION INPUT ;
    USE SIGNAL ;
    ANTENNAGATEAREA 0.213000 ;
    PORT
      LAYER met3 ;
        RECT 0.000 308.760 4.000 309.360 ;
    END
  END ten_mo[2]
  PIN ten_mo[3]
    DIRECTION INPUT ;
    USE SIGNAL ;
    ANTENNAGATEAREA 0.159000 ;
    PORT
      LAYER met3 ;
        RECT 0.000 315.560 4.000 316.160 ;
    END
  END ten_mo[3]
  PIN ten_s[0]
    DIRECTION INPUT ;
    USE SIGNAL ;
    ANTENNAGATEAREA 0.159000 ;
    PORT
      LAYER met3 ;
        RECT 0.000 77.560 4.000 78.160 ;
    END
  END ten_s[0]
  PIN ten_s[1]
    DIRECTION INPUT ;
    USE SIGNAL ;
    ANTENNAGATEAREA 0.159000 ;
    PORT
      LAYER met3 ;
        RECT 0.000 84.360 4.000 84.960 ;
    END
  END ten_s[1]
  PIN ten_s[2]
    DIRECTION INPUT ;
    USE SIGNAL ;
    ANTENNAGATEAREA 0.213000 ;
    PORT
      LAYER met3 ;
        RECT 0.000 91.160 4.000 91.760 ;
    END
  END ten_s[2]
  PIN ten_s[3]
    DIRECTION INPUT ;
    USE SIGNAL ;
    ANTENNAGATEAREA 0.213000 ;
    PORT
      LAYER met3 ;
        RECT 0.000 97.960 4.000 98.560 ;
    END
  END ten_s[3]
  PIN ten_y[0]
    DIRECTION INPUT ;
    USE SIGNAL ;
    ANTENNAGATEAREA 0.159000 ;
    PORT
      LAYER met3 ;
        RECT 0.000 349.560 4.000 350.160 ;
    END
  END ten_y[0]
  PIN ten_y[1]
    DIRECTION INPUT ;
    USE SIGNAL ;
    ANTENNAGATEAREA 0.213000 ;
    PORT
      LAYER met3 ;
        RECT 0.000 356.360 4.000 356.960 ;
    END
  END ten_y[1]
  PIN ten_y[2]
    DIRECTION INPUT ;
    USE SIGNAL ;
    ANTENNAGATEAREA 0.213000 ;
    PORT
      LAYER met3 ;
        RECT 0.000 363.160 4.000 363.760 ;
    END
  END ten_y[2]
  PIN ten_y[3]
    DIRECTION INPUT ;
    USE SIGNAL ;
    ANTENNAGATEAREA 0.159000 ;
    PORT
      LAYER met3 ;
        RECT 0.000 369.960 4.000 370.560 ;
    END
  END ten_y[3]
  PIN thou_y[0]
    DIRECTION INPUT ;
    USE SIGNAL ;
    ANTENNAGATEAREA 0.159000 ;
    PORT
      LAYER met3 ;
        RECT 0.000 403.960 4.000 404.560 ;
    END
  END thou_y[0]
  PIN thou_y[1]
    DIRECTION INPUT ;
    USE SIGNAL ;
    ANTENNAGATEAREA 0.213000 ;
    PORT
      LAYER met3 ;
        RECT 0.000 410.760 4.000 411.360 ;
    END
  END thou_y[1]
  PIN thou_y[2]
    DIRECTION INPUT ;
    USE SIGNAL ;
    ANTENNAGATEAREA 0.213000 ;
    PORT
      LAYER met3 ;
        RECT 0.000 417.560 4.000 418.160 ;
    END
  END thou_y[2]
  PIN thou_y[3]
    DIRECTION INPUT ;
    USE SIGNAL ;
    ANTENNAGATEAREA 0.213000 ;
    PORT
      LAYER met3 ;
        RECT 0.000 424.360 4.000 424.960 ;
    END
  END thou_y[3]
  PIN unit_d[0]
    DIRECTION INPUT ;
    USE SIGNAL ;
    ANTENNAGATEAREA 0.213000 ;
    PORT
      LAYER met3 ;
        RECT 0.000 213.560 4.000 214.160 ;
    END
  END unit_d[0]
  PIN unit_d[1]
    DIRECTION INPUT ;
    USE SIGNAL ;
    ANTENNAGATEAREA 0.159000 ;
    PORT
      LAYER met3 ;
        RECT 0.000 220.360 4.000 220.960 ;
    END
  END unit_d[1]
  PIN unit_d[2]
    DIRECTION INPUT ;
    USE SIGNAL ;
    ANTENNAGATEAREA 0.159000 ;
    PORT
      LAYER met3 ;
        RECT 0.000 227.160 4.000 227.760 ;
    END
  END unit_d[2]
  PIN unit_d[3]
    DIRECTION INPUT ;
    USE SIGNAL ;
    ANTENNAGATEAREA 0.159000 ;
    PORT
      LAYER met3 ;
        RECT 0.000 233.960 4.000 234.560 ;
    END
  END unit_d[3]
  PIN unit_h[0]
    DIRECTION INPUT ;
    USE SIGNAL ;
    ANTENNAGATEAREA 0.159000 ;
    PORT
      LAYER met3 ;
        RECT 0.000 159.160 4.000 159.760 ;
    END
  END unit_h[0]
  PIN unit_h[1]
    DIRECTION INPUT ;
    USE SIGNAL ;
    ANTENNAGATEAREA 0.213000 ;
    PORT
      LAYER met3 ;
        RECT 0.000 165.960 4.000 166.560 ;
    END
  END unit_h[1]
  PIN unit_h[2]
    DIRECTION INPUT ;
    USE SIGNAL ;
    ANTENNAGATEAREA 0.213000 ;
    PORT
      LAYER met3 ;
        RECT 0.000 172.760 4.000 173.360 ;
    END
  END unit_h[2]
  PIN unit_h[3]
    DIRECTION INPUT ;
    USE SIGNAL ;
    ANTENNAGATEAREA 0.213000 ;
    PORT
      LAYER met3 ;
        RECT 0.000 179.560 4.000 180.160 ;
    END
  END unit_h[3]
  PIN unit_h_alarm[0]
    DIRECTION INPUT ;
    USE SIGNAL ;
    ANTENNAGATEAREA 0.213000 ;
    PORT
      LAYER met3 ;
        RECT 0.000 485.560 4.000 486.160 ;
    END
  END unit_h_alarm[0]
  PIN unit_h_alarm[1]
    DIRECTION INPUT ;
    USE SIGNAL ;
    ANTENNAGATEAREA 0.159000 ;
    PORT
      LAYER met3 ;
        RECT 0.000 492.360 4.000 492.960 ;
    END
  END unit_h_alarm[1]
  PIN unit_h_alarm[2]
    DIRECTION INPUT ;
    USE SIGNAL ;
    ANTENNAGATEAREA 0.213000 ;
    PORT
      LAYER met3 ;
        RECT 0.000 499.160 4.000 499.760 ;
    END
  END unit_h_alarm[2]
  PIN unit_h_alarm[3]
    DIRECTION INPUT ;
    USE SIGNAL ;
    ANTENNAGATEAREA 0.159000 ;
    PORT
      LAYER met3 ;
        RECT 0.000 505.960 4.000 506.560 ;
    END
  END unit_h_alarm[3]
  PIN unit_m[0]
    DIRECTION INPUT ;
    USE SIGNAL ;
    ANTENNAGATEAREA 0.213000 ;
    PORT
      LAYER met3 ;
        RECT 0.000 104.760 4.000 105.360 ;
    END
  END unit_m[0]
  PIN unit_m[1]
    DIRECTION INPUT ;
    USE SIGNAL ;
    ANTENNAGATEAREA 0.213000 ;
    PORT
      LAYER met3 ;
        RECT 0.000 111.560 4.000 112.160 ;
    END
  END unit_m[1]
  PIN unit_m[2]
    DIRECTION INPUT ;
    USE SIGNAL ;
    ANTENNAGATEAREA 0.126000 ;
    PORT
      LAYER met3 ;
        RECT 0.000 118.360 4.000 118.960 ;
    END
  END unit_m[2]
  PIN unit_m[3]
    DIRECTION INPUT ;
    USE SIGNAL ;
    ANTENNAGATEAREA 0.196500 ;
    PORT
      LAYER met3 ;
        RECT 0.000 125.160 4.000 125.760 ;
    END
  END unit_m[3]
  PIN unit_m_alarm[0]
    DIRECTION INPUT ;
    USE SIGNAL ;
    ANTENNAGATEAREA 0.213000 ;
    PORT
      LAYER met3 ;
        RECT 0.000 431.160 4.000 431.760 ;
    END
  END unit_m_alarm[0]
  PIN unit_m_alarm[1]
    DIRECTION INPUT ;
    USE SIGNAL ;
    ANTENNAGATEAREA 0.213000 ;
    PORT
      LAYER met3 ;
        RECT 0.000 437.960 4.000 438.560 ;
    END
  END unit_m_alarm[1]
  PIN unit_m_alarm[2]
    DIRECTION INPUT ;
    USE SIGNAL ;
    ANTENNAGATEAREA 0.159000 ;
    PORT
      LAYER met3 ;
        RECT 0.000 444.760 4.000 445.360 ;
    END
  END unit_m_alarm[2]
  PIN unit_m_alarm[3]
    DIRECTION INPUT ;
    USE SIGNAL ;
    ANTENNAGATEAREA 0.159000 ;
    PORT
      LAYER met3 ;
        RECT 0.000 451.560 4.000 452.160 ;
    END
  END unit_m_alarm[3]
  PIN unit_mo[0]
    DIRECTION INPUT ;
    USE SIGNAL ;
    ANTENNAGATEAREA 0.159000 ;
    PORT
      LAYER met3 ;
        RECT 0.000 267.960 4.000 268.560 ;
    END
  END unit_mo[0]
  PIN unit_mo[1]
    DIRECTION INPUT ;
    USE SIGNAL ;
    ANTENNAGATEAREA 0.159000 ;
    PORT
      LAYER met3 ;
        RECT 0.000 274.760 4.000 275.360 ;
    END
  END unit_mo[1]
  PIN unit_mo[2]
    DIRECTION INPUT ;
    USE SIGNAL ;
    ANTENNAGATEAREA 0.213000 ;
    PORT
      LAYER met3 ;
        RECT 0.000 281.560 4.000 282.160 ;
    END
  END unit_mo[2]
  PIN unit_mo[3]
    DIRECTION INPUT ;
    USE SIGNAL ;
    ANTENNAGATEAREA 0.159000 ;
    PORT
      LAYER met3 ;
        RECT 0.000 288.360 4.000 288.960 ;
    END
  END unit_mo[3]
  PIN unit_s[0]
    DIRECTION INPUT ;
    USE SIGNAL ;
    ANTENNAGATEAREA 0.213000 ;
    PORT
      LAYER met3 ;
        RECT 0.000 50.360 4.000 50.960 ;
    END
  END unit_s[0]
  PIN unit_s[1]
    DIRECTION INPUT ;
    USE SIGNAL ;
    ANTENNAGATEAREA 0.213000 ;
    PORT
      LAYER met3 ;
        RECT 0.000 57.160 4.000 57.760 ;
    END
  END unit_s[1]
  PIN unit_s[2]
    DIRECTION INPUT ;
    USE SIGNAL ;
    ANTENNAGATEAREA 0.126000 ;
    PORT
      LAYER met3 ;
        RECT 0.000 63.960 4.000 64.560 ;
    END
  END unit_s[2]
  PIN unit_s[3]
    DIRECTION INPUT ;
    USE SIGNAL ;
    ANTENNAGATEAREA 0.213000 ;
    PORT
      LAYER met3 ;
        RECT 0.000 70.760 4.000 71.360 ;
    END
  END unit_s[3]
  PIN unit_y[0]
    DIRECTION INPUT ;
    USE SIGNAL ;
    ANTENNAGATEAREA 0.159000 ;
    PORT
      LAYER met3 ;
        RECT 0.000 322.360 4.000 322.960 ;
    END
  END unit_y[0]
  PIN unit_y[1]
    DIRECTION INPUT ;
    USE SIGNAL ;
    ANTENNAGATEAREA 0.213000 ;
    PORT
      LAYER met3 ;
        RECT 0.000 329.160 4.000 329.760 ;
    END
  END unit_y[1]
  PIN unit_y[2]
    DIRECTION INPUT ;
    USE SIGNAL ;
    ANTENNAGATEAREA 0.213000 ;
    PORT
      LAYER met3 ;
        RECT 0.000 335.960 4.000 336.560 ;
    END
  END unit_y[2]
  PIN unit_y[3]
    DIRECTION INPUT ;
    USE SIGNAL ;
    ANTENNAGATEAREA 0.213000 ;
    PORT
      LAYER met3 ;
        RECT 0.000 342.760 4.000 343.360 ;
    END
  END unit_y[3]
  OBS
      LAYER nwell ;
        RECT 5.330 10.795 94.490 587.605 ;
      LAYER li1 ;
        RECT 5.520 10.795 94.300 587.605 ;
      LAYER met1 ;
        RECT 4.210 10.640 94.300 587.760 ;
      LAYER met2 ;
        RECT 4.230 10.695 92.830 587.705 ;
      LAYER met3 ;
        RECT 3.990 585.840 96.000 587.685 ;
        RECT 3.990 584.440 95.600 585.840 ;
        RECT 3.990 580.400 96.000 584.440 ;
        RECT 3.990 579.000 95.600 580.400 ;
        RECT 3.990 574.960 96.000 579.000 ;
        RECT 3.990 573.560 95.600 574.960 ;
        RECT 3.990 569.520 96.000 573.560 ;
        RECT 3.990 568.120 95.600 569.520 ;
        RECT 3.990 564.080 96.000 568.120 ;
        RECT 3.990 562.680 95.600 564.080 ;
        RECT 3.990 561.360 96.000 562.680 ;
        RECT 4.400 559.960 96.000 561.360 ;
        RECT 3.990 558.640 96.000 559.960 ;
        RECT 3.990 557.240 95.600 558.640 ;
        RECT 3.990 554.560 96.000 557.240 ;
        RECT 4.400 553.200 96.000 554.560 ;
        RECT 4.400 553.160 95.600 553.200 ;
        RECT 3.990 551.800 95.600 553.160 ;
        RECT 3.990 547.760 96.000 551.800 ;
        RECT 4.400 546.360 95.600 547.760 ;
        RECT 3.990 542.320 96.000 546.360 ;
        RECT 3.990 540.960 95.600 542.320 ;
        RECT 4.400 540.920 95.600 540.960 ;
        RECT 4.400 539.560 96.000 540.920 ;
        RECT 3.990 536.880 96.000 539.560 ;
        RECT 3.990 535.480 95.600 536.880 ;
        RECT 3.990 534.160 96.000 535.480 ;
        RECT 4.400 532.760 96.000 534.160 ;
        RECT 3.990 531.440 96.000 532.760 ;
        RECT 3.990 530.040 95.600 531.440 ;
        RECT 3.990 527.360 96.000 530.040 ;
        RECT 4.400 526.000 96.000 527.360 ;
        RECT 4.400 525.960 95.600 526.000 ;
        RECT 3.990 524.600 95.600 525.960 ;
        RECT 3.990 520.560 96.000 524.600 ;
        RECT 4.400 519.160 95.600 520.560 ;
        RECT 3.990 515.120 96.000 519.160 ;
        RECT 3.990 513.760 95.600 515.120 ;
        RECT 4.400 513.720 95.600 513.760 ;
        RECT 4.400 512.360 96.000 513.720 ;
        RECT 3.990 509.680 96.000 512.360 ;
        RECT 3.990 508.280 95.600 509.680 ;
        RECT 3.990 506.960 96.000 508.280 ;
        RECT 4.400 505.560 96.000 506.960 ;
        RECT 3.990 504.240 96.000 505.560 ;
        RECT 3.990 502.840 95.600 504.240 ;
        RECT 3.990 500.160 96.000 502.840 ;
        RECT 4.400 498.800 96.000 500.160 ;
        RECT 4.400 498.760 95.600 498.800 ;
        RECT 3.990 497.400 95.600 498.760 ;
        RECT 3.990 493.360 96.000 497.400 ;
        RECT 4.400 491.960 95.600 493.360 ;
        RECT 3.990 487.920 96.000 491.960 ;
        RECT 3.990 486.560 95.600 487.920 ;
        RECT 4.400 486.520 95.600 486.560 ;
        RECT 4.400 485.160 96.000 486.520 ;
        RECT 3.990 482.480 96.000 485.160 ;
        RECT 3.990 481.080 95.600 482.480 ;
        RECT 3.990 479.760 96.000 481.080 ;
        RECT 4.400 478.360 96.000 479.760 ;
        RECT 3.990 477.040 96.000 478.360 ;
        RECT 3.990 475.640 95.600 477.040 ;
        RECT 3.990 472.960 96.000 475.640 ;
        RECT 4.400 471.600 96.000 472.960 ;
        RECT 4.400 471.560 95.600 471.600 ;
        RECT 3.990 470.200 95.600 471.560 ;
        RECT 3.990 466.160 96.000 470.200 ;
        RECT 4.400 464.760 95.600 466.160 ;
        RECT 3.990 460.720 96.000 464.760 ;
        RECT 3.990 459.360 95.600 460.720 ;
        RECT 4.400 459.320 95.600 459.360 ;
        RECT 4.400 457.960 96.000 459.320 ;
        RECT 3.990 455.280 96.000 457.960 ;
        RECT 3.990 453.880 95.600 455.280 ;
        RECT 3.990 452.560 96.000 453.880 ;
        RECT 4.400 451.160 96.000 452.560 ;
        RECT 3.990 449.840 96.000 451.160 ;
        RECT 3.990 448.440 95.600 449.840 ;
        RECT 3.990 445.760 96.000 448.440 ;
        RECT 4.400 444.400 96.000 445.760 ;
        RECT 4.400 444.360 95.600 444.400 ;
        RECT 3.990 443.000 95.600 444.360 ;
        RECT 3.990 438.960 96.000 443.000 ;
        RECT 4.400 437.560 95.600 438.960 ;
        RECT 3.990 433.520 96.000 437.560 ;
        RECT 3.990 432.160 95.600 433.520 ;
        RECT 4.400 432.120 95.600 432.160 ;
        RECT 4.400 430.760 96.000 432.120 ;
        RECT 3.990 428.080 96.000 430.760 ;
        RECT 3.990 426.680 95.600 428.080 ;
        RECT 3.990 425.360 96.000 426.680 ;
        RECT 4.400 423.960 96.000 425.360 ;
        RECT 3.990 422.640 96.000 423.960 ;
        RECT 3.990 421.240 95.600 422.640 ;
        RECT 3.990 418.560 96.000 421.240 ;
        RECT 4.400 417.200 96.000 418.560 ;
        RECT 4.400 417.160 95.600 417.200 ;
        RECT 3.990 415.800 95.600 417.160 ;
        RECT 3.990 411.760 96.000 415.800 ;
        RECT 4.400 410.360 95.600 411.760 ;
        RECT 3.990 406.320 96.000 410.360 ;
        RECT 3.990 404.960 95.600 406.320 ;
        RECT 4.400 404.920 95.600 404.960 ;
        RECT 4.400 403.560 96.000 404.920 ;
        RECT 3.990 400.880 96.000 403.560 ;
        RECT 3.990 399.480 95.600 400.880 ;
        RECT 3.990 398.160 96.000 399.480 ;
        RECT 4.400 396.760 96.000 398.160 ;
        RECT 3.990 395.440 96.000 396.760 ;
        RECT 3.990 394.040 95.600 395.440 ;
        RECT 3.990 391.360 96.000 394.040 ;
        RECT 4.400 390.000 96.000 391.360 ;
        RECT 4.400 389.960 95.600 390.000 ;
        RECT 3.990 388.600 95.600 389.960 ;
        RECT 3.990 384.560 96.000 388.600 ;
        RECT 4.400 383.160 95.600 384.560 ;
        RECT 3.990 379.120 96.000 383.160 ;
        RECT 3.990 377.760 95.600 379.120 ;
        RECT 4.400 377.720 95.600 377.760 ;
        RECT 4.400 376.360 96.000 377.720 ;
        RECT 3.990 373.680 96.000 376.360 ;
        RECT 3.990 372.280 95.600 373.680 ;
        RECT 3.990 370.960 96.000 372.280 ;
        RECT 4.400 369.560 96.000 370.960 ;
        RECT 3.990 368.240 96.000 369.560 ;
        RECT 3.990 366.840 95.600 368.240 ;
        RECT 3.990 364.160 96.000 366.840 ;
        RECT 4.400 362.800 96.000 364.160 ;
        RECT 4.400 362.760 95.600 362.800 ;
        RECT 3.990 361.400 95.600 362.760 ;
        RECT 3.990 357.360 96.000 361.400 ;
        RECT 4.400 355.960 95.600 357.360 ;
        RECT 3.990 351.920 96.000 355.960 ;
        RECT 3.990 350.560 95.600 351.920 ;
        RECT 4.400 350.520 95.600 350.560 ;
        RECT 4.400 349.160 96.000 350.520 ;
        RECT 3.990 346.480 96.000 349.160 ;
        RECT 3.990 345.080 95.600 346.480 ;
        RECT 3.990 343.760 96.000 345.080 ;
        RECT 4.400 342.360 96.000 343.760 ;
        RECT 3.990 341.040 96.000 342.360 ;
        RECT 3.990 339.640 95.600 341.040 ;
        RECT 3.990 336.960 96.000 339.640 ;
        RECT 4.400 335.600 96.000 336.960 ;
        RECT 4.400 335.560 95.600 335.600 ;
        RECT 3.990 334.200 95.600 335.560 ;
        RECT 3.990 330.160 96.000 334.200 ;
        RECT 4.400 328.760 95.600 330.160 ;
        RECT 3.990 324.720 96.000 328.760 ;
        RECT 3.990 323.360 95.600 324.720 ;
        RECT 4.400 323.320 95.600 323.360 ;
        RECT 4.400 321.960 96.000 323.320 ;
        RECT 3.990 319.280 96.000 321.960 ;
        RECT 3.990 317.880 95.600 319.280 ;
        RECT 3.990 316.560 96.000 317.880 ;
        RECT 4.400 315.160 96.000 316.560 ;
        RECT 3.990 313.840 96.000 315.160 ;
        RECT 3.990 312.440 95.600 313.840 ;
        RECT 3.990 309.760 96.000 312.440 ;
        RECT 4.400 308.400 96.000 309.760 ;
        RECT 4.400 308.360 95.600 308.400 ;
        RECT 3.990 307.000 95.600 308.360 ;
        RECT 3.990 302.960 96.000 307.000 ;
        RECT 4.400 301.560 95.600 302.960 ;
        RECT 3.990 297.520 96.000 301.560 ;
        RECT 3.990 296.160 95.600 297.520 ;
        RECT 4.400 296.120 95.600 296.160 ;
        RECT 4.400 294.760 96.000 296.120 ;
        RECT 3.990 292.080 96.000 294.760 ;
        RECT 3.990 290.680 95.600 292.080 ;
        RECT 3.990 289.360 96.000 290.680 ;
        RECT 4.400 287.960 96.000 289.360 ;
        RECT 3.990 286.640 96.000 287.960 ;
        RECT 3.990 285.240 95.600 286.640 ;
        RECT 3.990 282.560 96.000 285.240 ;
        RECT 4.400 281.200 96.000 282.560 ;
        RECT 4.400 281.160 95.600 281.200 ;
        RECT 3.990 279.800 95.600 281.160 ;
        RECT 3.990 275.760 96.000 279.800 ;
        RECT 4.400 274.360 95.600 275.760 ;
        RECT 3.990 270.320 96.000 274.360 ;
        RECT 3.990 268.960 95.600 270.320 ;
        RECT 4.400 268.920 95.600 268.960 ;
        RECT 4.400 267.560 96.000 268.920 ;
        RECT 3.990 264.880 96.000 267.560 ;
        RECT 3.990 263.480 95.600 264.880 ;
        RECT 3.990 262.160 96.000 263.480 ;
        RECT 4.400 260.760 96.000 262.160 ;
        RECT 3.990 259.440 96.000 260.760 ;
        RECT 3.990 258.040 95.600 259.440 ;
        RECT 3.990 255.360 96.000 258.040 ;
        RECT 4.400 254.000 96.000 255.360 ;
        RECT 4.400 253.960 95.600 254.000 ;
        RECT 3.990 252.600 95.600 253.960 ;
        RECT 3.990 248.560 96.000 252.600 ;
        RECT 4.400 247.160 95.600 248.560 ;
        RECT 3.990 243.120 96.000 247.160 ;
        RECT 3.990 241.760 95.600 243.120 ;
        RECT 4.400 241.720 95.600 241.760 ;
        RECT 4.400 240.360 96.000 241.720 ;
        RECT 3.990 237.680 96.000 240.360 ;
        RECT 3.990 236.280 95.600 237.680 ;
        RECT 3.990 234.960 96.000 236.280 ;
        RECT 4.400 233.560 96.000 234.960 ;
        RECT 3.990 232.240 96.000 233.560 ;
        RECT 3.990 230.840 95.600 232.240 ;
        RECT 3.990 228.160 96.000 230.840 ;
        RECT 4.400 226.800 96.000 228.160 ;
        RECT 4.400 226.760 95.600 226.800 ;
        RECT 3.990 225.400 95.600 226.760 ;
        RECT 3.990 221.360 96.000 225.400 ;
        RECT 4.400 219.960 95.600 221.360 ;
        RECT 3.990 215.920 96.000 219.960 ;
        RECT 3.990 214.560 95.600 215.920 ;
        RECT 4.400 214.520 95.600 214.560 ;
        RECT 4.400 213.160 96.000 214.520 ;
        RECT 3.990 210.480 96.000 213.160 ;
        RECT 3.990 209.080 95.600 210.480 ;
        RECT 3.990 207.760 96.000 209.080 ;
        RECT 4.400 206.360 96.000 207.760 ;
        RECT 3.990 205.040 96.000 206.360 ;
        RECT 3.990 203.640 95.600 205.040 ;
        RECT 3.990 200.960 96.000 203.640 ;
        RECT 4.400 199.600 96.000 200.960 ;
        RECT 4.400 199.560 95.600 199.600 ;
        RECT 3.990 198.200 95.600 199.560 ;
        RECT 3.990 194.160 96.000 198.200 ;
        RECT 4.400 192.760 95.600 194.160 ;
        RECT 3.990 188.720 96.000 192.760 ;
        RECT 3.990 187.360 95.600 188.720 ;
        RECT 4.400 187.320 95.600 187.360 ;
        RECT 4.400 185.960 96.000 187.320 ;
        RECT 3.990 183.280 96.000 185.960 ;
        RECT 3.990 181.880 95.600 183.280 ;
        RECT 3.990 180.560 96.000 181.880 ;
        RECT 4.400 179.160 96.000 180.560 ;
        RECT 3.990 177.840 96.000 179.160 ;
        RECT 3.990 176.440 95.600 177.840 ;
        RECT 3.990 173.760 96.000 176.440 ;
        RECT 4.400 172.400 96.000 173.760 ;
        RECT 4.400 172.360 95.600 172.400 ;
        RECT 3.990 171.000 95.600 172.360 ;
        RECT 3.990 166.960 96.000 171.000 ;
        RECT 4.400 165.560 95.600 166.960 ;
        RECT 3.990 161.520 96.000 165.560 ;
        RECT 3.990 160.160 95.600 161.520 ;
        RECT 4.400 160.120 95.600 160.160 ;
        RECT 4.400 158.760 96.000 160.120 ;
        RECT 3.990 156.080 96.000 158.760 ;
        RECT 3.990 154.680 95.600 156.080 ;
        RECT 3.990 153.360 96.000 154.680 ;
        RECT 4.400 151.960 96.000 153.360 ;
        RECT 3.990 150.640 96.000 151.960 ;
        RECT 3.990 149.240 95.600 150.640 ;
        RECT 3.990 146.560 96.000 149.240 ;
        RECT 4.400 145.200 96.000 146.560 ;
        RECT 4.400 145.160 95.600 145.200 ;
        RECT 3.990 143.800 95.600 145.160 ;
        RECT 3.990 139.760 96.000 143.800 ;
        RECT 4.400 138.360 95.600 139.760 ;
        RECT 3.990 134.320 96.000 138.360 ;
        RECT 3.990 132.960 95.600 134.320 ;
        RECT 4.400 132.920 95.600 132.960 ;
        RECT 4.400 131.560 96.000 132.920 ;
        RECT 3.990 128.880 96.000 131.560 ;
        RECT 3.990 127.480 95.600 128.880 ;
        RECT 3.990 126.160 96.000 127.480 ;
        RECT 4.400 124.760 96.000 126.160 ;
        RECT 3.990 123.440 96.000 124.760 ;
        RECT 3.990 122.040 95.600 123.440 ;
        RECT 3.990 119.360 96.000 122.040 ;
        RECT 4.400 118.000 96.000 119.360 ;
        RECT 4.400 117.960 95.600 118.000 ;
        RECT 3.990 116.600 95.600 117.960 ;
        RECT 3.990 112.560 96.000 116.600 ;
        RECT 4.400 111.160 95.600 112.560 ;
        RECT 3.990 107.120 96.000 111.160 ;
        RECT 3.990 105.760 95.600 107.120 ;
        RECT 4.400 105.720 95.600 105.760 ;
        RECT 4.400 104.360 96.000 105.720 ;
        RECT 3.990 101.680 96.000 104.360 ;
        RECT 3.990 100.280 95.600 101.680 ;
        RECT 3.990 98.960 96.000 100.280 ;
        RECT 4.400 97.560 96.000 98.960 ;
        RECT 3.990 96.240 96.000 97.560 ;
        RECT 3.990 94.840 95.600 96.240 ;
        RECT 3.990 92.160 96.000 94.840 ;
        RECT 4.400 90.800 96.000 92.160 ;
        RECT 4.400 90.760 95.600 90.800 ;
        RECT 3.990 89.400 95.600 90.760 ;
        RECT 3.990 85.360 96.000 89.400 ;
        RECT 4.400 83.960 95.600 85.360 ;
        RECT 3.990 79.920 96.000 83.960 ;
        RECT 3.990 78.560 95.600 79.920 ;
        RECT 4.400 78.520 95.600 78.560 ;
        RECT 4.400 77.160 96.000 78.520 ;
        RECT 3.990 74.480 96.000 77.160 ;
        RECT 3.990 73.080 95.600 74.480 ;
        RECT 3.990 71.760 96.000 73.080 ;
        RECT 4.400 70.360 96.000 71.760 ;
        RECT 3.990 69.040 96.000 70.360 ;
        RECT 3.990 67.640 95.600 69.040 ;
        RECT 3.990 64.960 96.000 67.640 ;
        RECT 4.400 63.600 96.000 64.960 ;
        RECT 4.400 63.560 95.600 63.600 ;
        RECT 3.990 62.200 95.600 63.560 ;
        RECT 3.990 58.160 96.000 62.200 ;
        RECT 4.400 56.760 95.600 58.160 ;
        RECT 3.990 52.720 96.000 56.760 ;
        RECT 3.990 51.360 95.600 52.720 ;
        RECT 4.400 51.320 95.600 51.360 ;
        RECT 4.400 49.960 96.000 51.320 ;
        RECT 3.990 47.280 96.000 49.960 ;
        RECT 3.990 45.880 95.600 47.280 ;
        RECT 3.990 44.560 96.000 45.880 ;
        RECT 4.400 43.160 96.000 44.560 ;
        RECT 3.990 41.840 96.000 43.160 ;
        RECT 3.990 40.440 95.600 41.840 ;
        RECT 3.990 37.760 96.000 40.440 ;
        RECT 4.400 36.400 96.000 37.760 ;
        RECT 4.400 36.360 95.600 36.400 ;
        RECT 3.990 35.000 95.600 36.360 ;
        RECT 3.990 30.960 96.000 35.000 ;
        RECT 3.990 29.560 95.600 30.960 ;
        RECT 3.990 25.520 96.000 29.560 ;
        RECT 3.990 24.120 95.600 25.520 ;
        RECT 3.990 20.080 96.000 24.120 ;
        RECT 3.990 18.680 95.600 20.080 ;
        RECT 3.990 14.640 96.000 18.680 ;
        RECT 3.990 13.240 95.600 14.640 ;
        RECT 3.990 10.715 96.000 13.240 ;
      LAYER met4 ;
        RECT 7.655 157.935 8.905 476.505 ;
  END
END top_display
END LIBRARY

